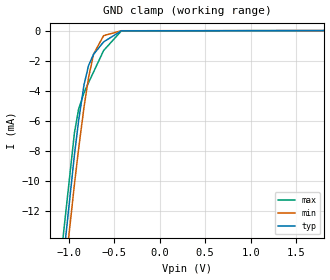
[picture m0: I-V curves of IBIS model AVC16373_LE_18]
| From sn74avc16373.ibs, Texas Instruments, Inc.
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[Model]   AVC16373_LE_18
Model_type  Input
Vinl=0.5775
Vinh=1.2675
| variable   typ   min   max
C_comp   1.18pF   0.99pF   1.35pF
[Temperature Range]   40   100   -40
| Ambient temperature   25   85   -40
[Voltage range]   1.8   1.65   1.95
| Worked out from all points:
|   GND clamp passes 1 mA (typ) near -0.65 V on its own axis
[GND Clamp]
| AVC16373_LE_18
|   Voltage   I(typ)   I(min)   I(max)
-1.8V     -63.88mA   -63.41mA   -65.81mA
-1.125V   -19.32mA   -20.97mA   -17.91mA
-1.095V   -17.47mA   -19.2mA    -15.95mA
-1.065V   -15.65mA   -17.45mA   -14.03mA
-935mV    -8.251mA   -10.21mA   -6.785mA
-890mV    -6.02mA    -7.895mA   -5.239mA
-830mV    -3.604mA   -5.085mA   -4.126mA
-780mV    -2.319mA   -3.12mA    -3.454mA
-725mV    -1.575mA   -1.563mA   -2.747mA
-615mV    -751.2uA   -336.4uA   -1.327mA
-420mV    -16.5uA    -10.21uA   -21.14uA
1.8V      199.5pA    671.8pA    9.677pA
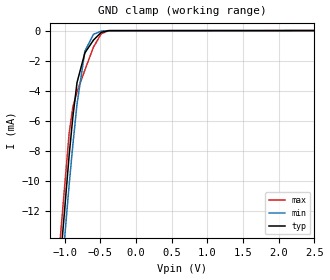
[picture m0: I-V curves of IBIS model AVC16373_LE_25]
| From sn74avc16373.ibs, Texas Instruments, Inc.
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[Model]   AVC16373_LE_25
Model_type  Input
Vinl=0.7
Vinh=1.7
| variable   typ   min   max
C_comp   1.17pF   0.97pF   1.42pF
[Temperature Range]   40   100   -40
| Ambient temperature   25   85   -40
[Voltage range]   2.5   2.3   2.7
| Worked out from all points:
|   GND clamp passes 1 mA (typ) near -0.65 V on its own axis
[GND Clamp]
| AVC16373_LE_25
|   Voltage   I(typ)   I(min)   I(max)
-2.5V     -112.2mA   -109.4mA   -117.8mA
-1.135V   -19.94mA   -21.57mA   -18.57mA
-1.1V     -17.78mA   -19.5mA    -16.27mA
-1.07V    -15.95mA   -17.74mA   -14.34mA
-935mV    -8.251mA   -10.21mA   -6.785mA
-885mV    -5.791mA   -7.647mA   -5.114mA
-825mV    -3.443mA   -4.871mA   -4.055mA
-715mV    -1.48mA    -1.36mA    -2.619mA
-595mV    -630.8uA   -252uA     -1.097mA
-485mV    -114.4uA   -29.54uA   -203.1uA
-380mV    -5.562uA   -4.599uA   -5.667uA
2.5V      206.6pA    685.3pA    11.37pA
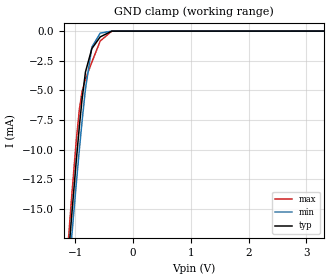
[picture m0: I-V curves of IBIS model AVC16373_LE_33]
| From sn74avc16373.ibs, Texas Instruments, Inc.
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[Model]   AVC16373_LE_33
Model_type  Input
Vinl=0.8
Vinh=2
| variable   typ   min   max
C_comp   1.17pF   0.93pF   1.44pF
[Temperature Range]   40   100   -40
| Ambient temperature   25   85   -40
[Voltage range]   3.3   3   3.6
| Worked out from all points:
|   GND clamp passes 1 mA (typ) near -0.65 V on its own axis
[GND Clamp]
| AVC16373_LE_33
|   Voltage   I(typ)   I(min)   I(max)
-3.3V     -168.4mA   -162.8mA   -178.2mA
-1.12V    -19.01mA   -20.68mA   -17.58mA
-1.1V     -17.78mA   -19.5mA    -16.27mA
-1.065V   -15.65mA   -17.45mA   -14.03mA
-985mV    -10.97mA   -12.91mA   -9.257mA
-930mV    -7.991mA   -9.944mA   -6.576mA
-885mV    -5.791mA   -7.647mA   -5.114mA
-825mV    -3.443mA   -4.871mA   -4.055mA
-715mV    -1.48mA    -1.36mA    -2.619mA
-570mV    -489.8uA   -169.9uA   -837.3uA
-370mV    -4.236uA   -3.71uA    -3.93uA
3.3V      214.2pA    699.5pA    13.28pA
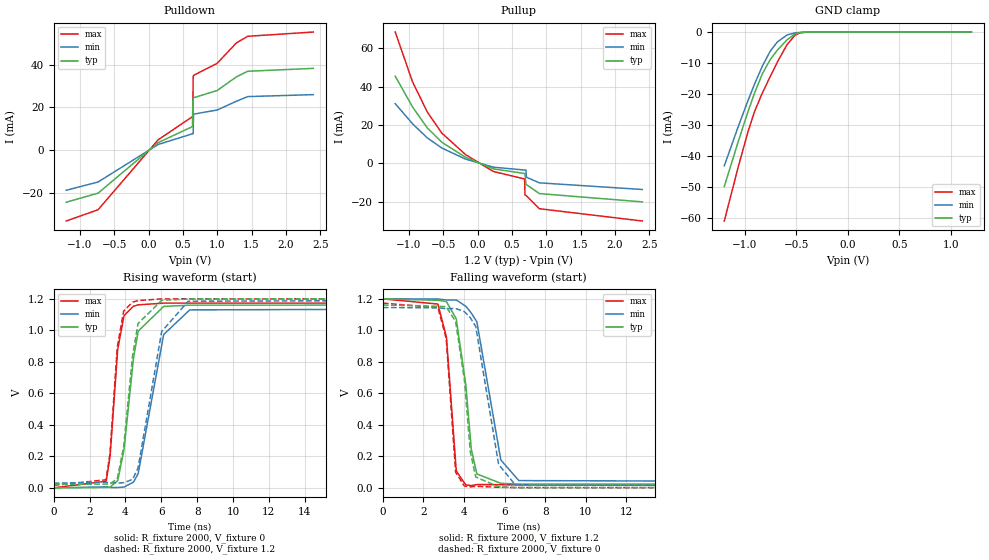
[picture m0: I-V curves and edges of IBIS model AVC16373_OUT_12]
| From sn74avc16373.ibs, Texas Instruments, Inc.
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[Model]   AVC16373_OUT_12
Model_type  3-state
Enable   Active-Low
Vref =   0
Rref =   2000
Cref =   15p
Vmeas =   0.6
| variable   typ   min   max
C_comp   4.12pF   3.33pF   5.34pF
| C_pullup   2.76pF   0.17pF   6.41pF
| C_pulldown   4.92pF   0.64pF   13.12pF
| C_tri-state   4.12pF   3.33pF   5.34pF
[Temperature Range]   40   100   -40
| Ambient temperature   25   85   -40
[Voltage range]   1.2   1.2   1.2
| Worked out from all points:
|   slope of the pulldown table from 0 to 0.18 V, typ, clamps not added: 41.3 ohm
|   slope of the pullup table from 0 to 0.18 V, typ, clamps not added: 75.9 ohm
|   GND clamp passes 1 mA (typ) near -0.53 V on its own axis
|   rising waveform, R_fixture 2000, V_fixture 0: 20-80 % time 671ps typ, 965ps min, 460ps max; typ from 0 V to 1.16 V
|   falling waveform, R_fixture 2000, V_fixture 1.2: 20-80 % time 527ps typ, 810ps min, 374ps max; typ from 1.2 V to 0.022 V
|   rising waveform, R_fixture 2000, V_fixture 1.2: 20-80 % time 659ps typ, 947ps min, 448ps max; typ from 0.022 V to 1.2 V
|   falling waveform, R_fixture 2000, V_fixture 0: 20-80 % time 493ps typ, 732ps min, 351ps max; typ from 1.16 V to 0 V
[GND Clamp]
| AVC16373_OUT_12
|   Voltage   I(typ)   I(min)   I(max)
-1.2V     -49.81mA   -43.12mA   -60.93mA
-1.065V   -35.33mA   -30.53mA   -43.53mA
-970mV    -25.69mA   -22.11mA   -32.16mA
-905mV    -19.57mA   -16.69mA   -25.52mA
-830mV    -13.44mA   -10.97mA   -19.64mA
-755mV    -8.942mA   -6.236mA   -14.44mA
-685mV    -5.853mA   -3.205mA   -9.722mA
-590mV    -2.48mA    -945.2uA   -4.03mA
-510mV    -577uA     -252.2uA   -914.9uA
-455mV    -143.2uA   -104.1uA   -185.2uA
-385mV    -21.43uA   -28.66uA   -14.82uA
1.2V      906.5pA    4.013nA    28.85pA
[Pulldown]
| AVC16373_OUT_12
|   Voltage   I(typ)   I(min)   I(max)
-1.2V     -24.58mA   -18.95mA   -33.4mA
-735mV    -20.3mA    -15.06mA   -28.1mA
140mV     3.462mA    2.573mA    4.781mA
640mV     10.98mA    7.608mA    15.63mA
645mV     21.39mA    7.616mA    15.69mA
650mV     24.35mA    7.636mA    34.23mA
655mV     24.51mA    16.53mA    34.97mA
660mV     24.57mA    16.86mA    35.1mA
1V        27.94mA    18.77mA    40.73mA
1.28V     34.34mA    22.9mA     50.3mA
1.445V    36.98mA    25.07mA    53.42mA
2.4V      38.34mA    26mA       55.42mA
[Pullup]
| AVC16373_OUT_12
|   Voltage   I(typ)   I(min)   I(max)
-1.2V     45.51mA    31.17mA    68.58mA
-950mV    29.56mA    20.73mA    42.76mA
-735mV    18.6mA     13.35mA    26.89mA
-520mV    10.96mA    7.962mA    15.74mA
-175mV    3.153mA    2.205mA    4.538mA
230mV     -2.893mA   -2.023mA   -4.269mA
685mV     -5.328mA   -3.511mA   -8.179mA
690mV     -5.367mA   -3.522mA   -16.51mA
705mV     -11.02mA   -3.556mA   -16.81mA
710mV     -11.09mA   -7.24mA    -16.92mA
900mV     -15.81mA   -10.2mA    -23.72mA
2.4V      -20.15mA   -13.67mA   -30.14mA
[Ramp]
| AVC16373_OUT_12
| variable   typ   min   max
dV/dt_r   0.70/6.79E-10   0.69/9.69E-10   0.70/4.66E-10
dV/dt_f   0.71/5.34E-10   0.70/8.12E-10   0.71/3.84E-10
R_load = 2000
[Rising Waveform]
| AVC16373_OUT_12
R_fixture =   2000
C_fixture =   0
L_fixture =   0
V_fixture =   0
V_fixture_min = 0
V_fixture_max = 0
|   Time   V(typ)   V(min)   V(max)
0s        19.84nV    111.1nV    534pV
2.925ns   2.21mV     5.753mV    42.16mV
3.14ns    4.979mV    2.339mV    201.7mV
3.565ns   45.59mV    2.125mV    879mV
3.92ns    244.4mV    5.215mV    1.094V
4.445ns   823.1mV    36.22mV    1.153V
4.71ns    995.3mV    91.19mV    1.162V
6.13ns    1.152V     973.6mV    1.173V
7.585ns   1.16V      1.13V      1.173V
50ns      1.161V     1.145V     1.173V
[Falling Waveform]
| AVC16373_OUT_12
R_fixture =   2000
C_fixture =   0
L_fixture =   0
V_fixture =   1.2
V_fixture_min = 1.2
V_fixture_max = 1.2
|   Time   V(typ)   V(min)   V(max)
0s        1.2V       1.2V       1.2V
2.71ns    1.191V     1.199V     1.167V
3.13ns    1.183V     1.193V     958.4mV
3.615ns   1.073V     1.193V     107mV
4.085ns   653.7mV    1.153V     18.34mV
4.355ns   245.5mV    1.11V      14.31mV
4.63ns    88.18mV    1.054V     21mV
5.81ns    28.72mV    177.4mV    20.03mV
6.695ns   23.88mV    46.06mV    17.94mV
50ns      22.2mV     29.57mV    16.15mV
[Rising Waveform]
| AVC16373_OUT_12
R_fixture =   2000
C_fixture =   0
L_fixture =   0
V_fixture =   1.2
V_fixture_min = 1.2
V_fixture_max = 1.2
|   Time   V(typ)   V(min)   V(max)
0s        22.2mV     29.57mV    16.15mV
2.91ns    23.93mV    35.37mV    51.16mV
3.135ns   24.73mV    31.54mV    219mV
3.54ns    57.93mV    31.01mV    891mV
3.9ns     263.1mV    32.25mV    1.123V
4.395ns   839.5mV    53.88mV    1.179V
4.7ns     1.043V     125.2mV    1.189V
6.02ns    1.191V     992.7mV    1.2V
7.5ns     1.199V     1.185V     1.2V
50ns      1.2V       1.2V       1.2V
[Falling Waveform]
| AVC16373_OUT_12
R_fixture =   2000
C_fixture =   0
L_fixture =   0
V_fixture =   0
V_fixture_min = 0
V_fixture_max = 0
|   Time   V(typ)   V(min)   V(max)
0s        1.161V     1.145V     1.173V
2.715ns   1.153V     1.143V     1.145V
3.12ns    1.15V      1.138V     946.8mV
3.585ns   1.055V     1.139V     98.97mV
4.015ns   687.3mV    1.119V     11.04mV
4.305ns   229.3mV    1.081V     6.349mV
4.575ns   68.82mV    1.024V     9.649mV
5.7ns     6.452mV    148.9mV    3.582mV
6.525ns   1.658mV    18.38mV    1.675mV
50ns      30.29nV    53.14nV    -3.408nV
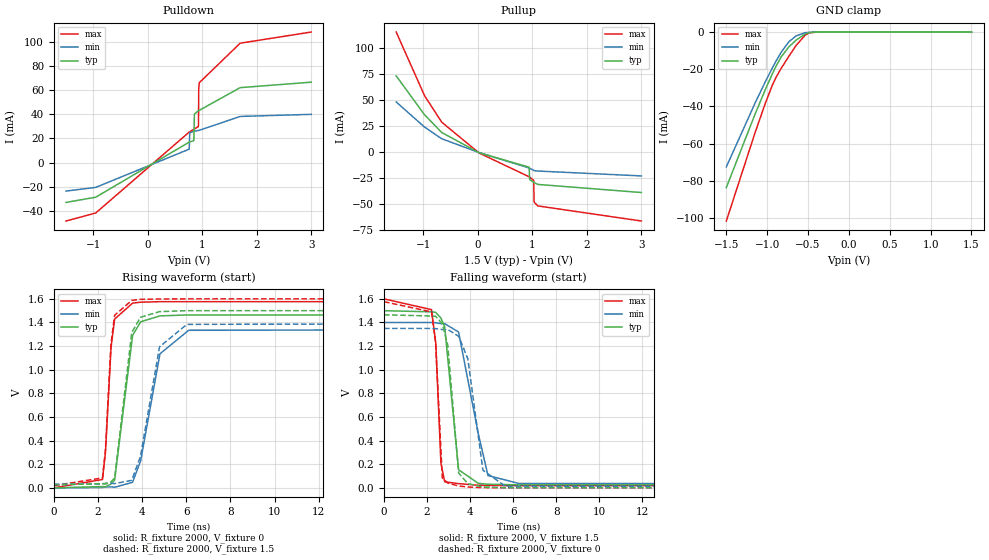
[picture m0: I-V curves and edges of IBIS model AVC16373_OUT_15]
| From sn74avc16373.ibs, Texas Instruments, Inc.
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[Model]   AVC16373_OUT_15
Model_type  3-state
Enable   Active-Low
Vref =   0
Rref =   2000
Cref =   15p
Vmeas =   0.75
| variable   typ   min   max
C_comp   4.31pF   3.38pF   5.88pF
| C_pullup   5.34pF   0.15pF   13.15pF
| C_pulldown   7.78pF   0.15pF   27.61pF
| C_tri-state   4.31pF   3.38pF   5.88pF
[Temperature Range]   40   100   -40
| Ambient temperature   25   85   -40
[Voltage range]   1.5   1.4   1.6
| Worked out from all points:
|   slope of the pulldown table from 0 to 0.225 V, typ, clamps not added: 36.1 ohm
|   slope of the pullup table from 0 to 0.225 V, typ, clamps not added: 53.5 ohm
|   GND clamp passes 1 mA (typ) near -0.53 V on its own axis
|   rising waveform, R_fixture 2000, V_fixture 0: 20-80 % time 468ps typ, 734ps min, 281ps max; typ from 0 V to 1.47 V
|   falling waveform, R_fixture 2000, V_fixture 1.5: 20-80 % time 357ps typ, 583ps min, 219ps max; typ from 1.5 V to 0.025 V
|   rising waveform, R_fixture 2000, V_fixture 1.5: 20-80 % time 452ps typ, 714ps min, 275ps max; typ from 0.025 V to 1.5 V
|   falling waveform, R_fixture 2000, V_fixture 0: 20-80 % time 346ps typ, 543ps min, 214ps max; typ from 1.47 V to 0 V
[GND Clamp]
| AVC16373_OUT_15
|   Voltage   I(typ)   I(min)   I(max)
-1.5V     -83.68mA   -72.57mA   -101.7mA
-1.15V    -44.37mA   -38.39mA   -54.38mA
-1.025V   -31.19mA   -26.93mA   -38.6mA
-940mV    -22.8mA    -19.57mA   -28.92mA
-890mV    -18.24mA   -15.49mA   -24.21mA
-830mV    -13.44mA   -10.97mA   -19.64mA
-735mV    -7.99mA    -5.222mA   -13.08mA
-645mV    -4.324mA   -2.052mA   -7.147mA
-535mV    -1.035mA   -358.6uA   -1.661mA
-485mV    -307.8uA   -166.7uA   -439.4uA
-395mV    -28.13uA   -35.17uA   -21.37uA
1.5V      923.6pA    11.37nA    28.98pA
[Pulldown]
| AVC16373_OUT_15
|   Voltage   I(typ)   I(min)   I(max)
-1.5V     -33mA      -23.61mA   -48.39mA
-955mV    -28.68mA   -20.56mA   -41.74mA
760mV     16.89mA    11.08mA    25.23mA
770mV     17.03mA    24.64mA    25.49mA
845mV     18.17mA    25.77mA    27.48mA
855mV     40.2mA     25.88mA    27.75mA
925mV     42.66mA    26.52mA    29.72mA
930mV     42.8mA     26.55mA    30.08mA
935mV     42.94mA    26.59mA    61.05mA
945mV     43.22mA    26.68mA    66.04mA
1.695V    61.97mA    38.15mA    98.75mA
3V        66.51mA    39.88mA    108mA
[Pullup]
| AVC16373_OUT_15
|   Voltage   I(typ)   I(min)   I(max)
-1.5V     73.5mA     48.38mA    115.7mA
-980mV    36.08mA    24.24mA    54.47mA
-665mV    19.05mA    13.02mA    28.99mA
20mV      -420.5uA   -275.9uA   -662.9uA
940mV     -14.35mA   -15.15mA   -23.58mA
950mV     -26.22mA   -15.4mA    -23.99mA
1.02V     -28.75mA   -17.27mA   -26.94mA
1.025V    -28.95mA   -17.41mA   -27.17mA
1.03V     -29.14mA   -17.56mA   -46.58mA
1.035V    -29.33mA   -17.7mA    -48.24mA
1.1V      -30.94mA   -18.07mA   -51.63mA
3V        -38.73mA   -22.77mA   -66.15mA
[Ramp]
| AVC16373_OUT_15
| variable   typ   min   max
dV/dt_r   0.88/4.71E-10   0.81/7.39E-10   0.95/2.88E-10
dV/dt_f   0.89/3.65E-10   0.82/5.91E-10   0.95/2.26E-10
R_load = 2000
[Rising Waveform]
| AVC16373_OUT_15
R_fixture =   2000
C_fixture =   0
L_fixture =   0
V_fixture =   0
V_fixture_min = 0
V_fixture_max = 0
|   Time   V(typ)   V(min)   V(max)
0s        20.21nV    106.8nV    637.5pV
2.205ns   10.56mV    2.702mV    70.63mV
2.34ns    8.447mV    7.294mV    300.7mV
2.595ns   32.66mV    8.339mV    1.193V
2.755ns   65.77mV    4.722mV    1.429V
3.57ns    1.291V     46.92mV    1.564V
3.935ns   1.406V     229.2mV    1.572V
4.81ns    1.456V     1.135V     1.576V
6.11ns    1.464V     1.334V     1.576V
50ns      1.465V     1.35V      1.576V
[Falling Waveform]
| AVC16373_OUT_15
R_fixture =   2000
C_fixture =   0
L_fixture =   0
V_fixture =   1.5
V_fixture_min = 1.4
V_fixture_max = 1.6
|   Time   V(typ)   V(min)   V(max)
0s        1.5V       1.4V       1.6V
2.205ns   1.49V      1.4V       1.509V
2.405ns   1.486V     1.398V     1.229V
2.645ns   1.437V     1.39V      205.8mV
2.82ns    1.364V     1.39V      51.59mV
3.465ns   153.2mV    1.319V     35.54mV
4.38ns    38.37mV    458.8mV    22.03mV
4.83ns    30.44mV    104.2mV    20.25mV
6.26ns    25.33mV    37.29mV    18.98mV
50ns      24.77mV    31.4mV     18.88mV
[Rising Waveform]
| AVC16373_OUT_15
R_fixture =   2000
C_fixture =   0
L_fixture =   0
V_fixture =   1.5
V_fixture_min = 1.4
V_fixture_max = 1.6
|   Time   V(typ)   V(min)   V(max)
0s        24.77mV    31.4mV     18.88mV
2.205ns   35.21mV    34.11mV    83.94mV
2.34ns    31.83mV    38.68mV    323.2mV
2.59ns    49.8mV     39.71mV    1.22V
2.755ns   83.91mV    35.8mV     1.461V
3.53ns    1.315V     63.65mV    1.587V
3.925ns   1.444V     264.8mV    1.596V
4.79ns    1.492V     1.194V     1.599V
6.03ns    1.5V       1.384V     1.6V
50ns      1.5V       1.4V       1.6V
[Falling Waveform]
| AVC16373_OUT_15
R_fixture =   2000
C_fixture =   0
L_fixture =   0
V_fixture =   0
V_fixture_min = 0
V_fixture_max = 0
|   Time   V(typ)   V(min)   V(max)
0s        1.465V     1.35V      1.576V
2.21ns    1.455V     1.35V      1.49V
2.4ns     1.453V     1.348V     1.222V
2.71ns    1.389V     1.34V      83.76mV
2.96ns    1.21V      1.341V     40.58mV
3.47ns    124.7mV    1.283V     15.63mV
3.895ns   35.89mV    1.093V     6.97mV
4.595ns   7.797mV    148.7mV    1.919mV
5.625ns   1.207mV    14.85mV    275.4uV
50ns      27.09nV    138.3nV    -888.7pV
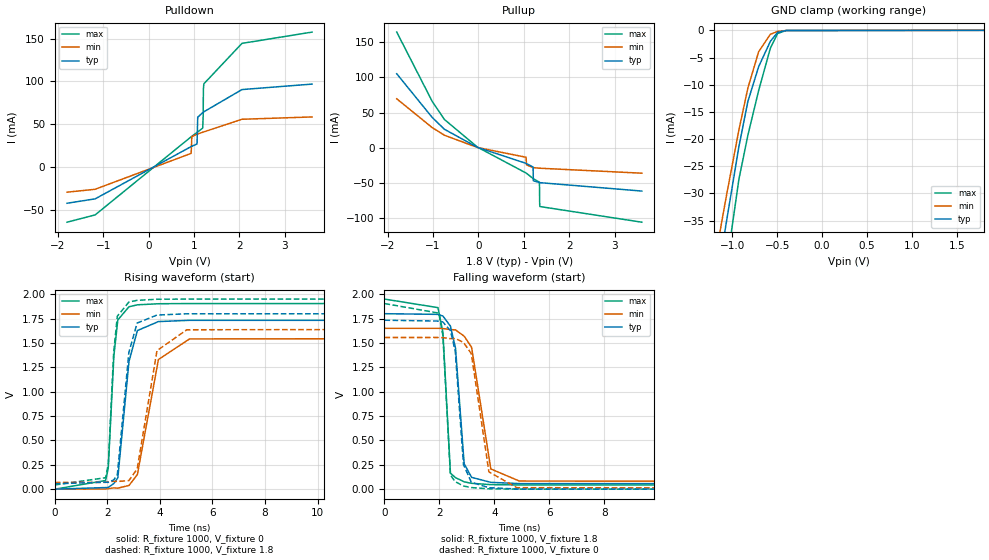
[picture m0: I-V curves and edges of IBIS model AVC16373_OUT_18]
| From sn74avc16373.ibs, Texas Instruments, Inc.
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[Model]   AVC16373_OUT_18
Model_type  3-state
Enable   Active-Low
Vref =   0
Rref =   1000
Cref =   30p
Vmeas =   0.9
| variable   typ   min   max
C_comp   4.32pF   3.35pF   5.68pF
| C_pullup   6.96pF   2.28pF   18.50pF
| C_pulldown   11.01pF   0.32pF   33.42pF
| C_tri-state   4.32pF   3.35pF   5.68pF
[Temperature Range]   40   100   -40
| Ambient temperature   25   85   -40
[Voltage range]   1.8   1.65   1.95
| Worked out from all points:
|   slope of the pulldown table from 0 to 0.27 V, typ, clamps not added: 33.5 ohm
|   slope of the pullup table from 0 to 0.27 V, typ, clamps not added: 42.5 ohm
|   GND clamp passes 1 mA (typ) near -0.53 V on its own axis
|   rising waveform, R_fixture 1000, V_fixture 0: 20-80 % time 351ps typ, 571ps min, 219ps max; typ from 0 V to 1.73 V
|   falling waveform, R_fixture 1000, V_fixture 1.8: 20-80 % time 263ps typ, 445ps min, 179ps max; typ from 1.8 V to 0.055 V
|   rising waveform, R_fixture 1000, V_fixture 1.8: 20-80 % time 330ps typ, 531ps min, 210ps max; typ from 0.055 V to 1.8 V
|   falling waveform, R_fixture 1000, V_fixture 0: 20-80 % time 253ps typ, 410ps min, 177ps max; typ from 1.73 V to 0 V
[GND Clamp]
| AVC16373_OUT_18
|   Voltage   I(typ)   I(min)   I(max)
-1.8V     -118.8mA   -103.2mA   -143.9mA
-1.215V   -51.46mA   -44.55mA   -62.92mA
-1.145V   -43.83mA   -37.92mA   -53.73mA
-1.085V   -37.42mA   -32.35mA   -46.04mA
-1.07V    -35.85mA   -30.98mA   -44.15mA
-925mV    -21.39mA   -18.32mA   -27.4mA
-825mV    -13.08mA   -10.61mA   -19.29mA
-705mV    -6.674mA   -3.926mA   -11.06mA
-575mV    -2.039mA   -729.4uA   -3.298mA
-495mV    -388.5uA   -195.8uA   -593.1uA
-400mV    -32.23uA   -38.84uA   -25.66uA
1.8V      940.2pA    10.95nA    32pA
[Pulldown]
| AVC16373_OUT_18
|   Voltage   I(typ)   I(min)   I(max)
-1.8V     -42.48mA   -29.53mA   -64.63mA
-1.18V    -37.33mA   -26.14mA   -56.11mA
935mV     23.8mA     15.87mA    35.26mA
950mV     24.14mA    35.36mA    35.83mA
1.065V    26.9mA     38.19mA    40.35mA
1.08V     58.17mA    38.51mA    40.96mA
1.19V     63.45mA    40.59mA    45.43mA
1.2V      63.85mA    40.76mA    59.33mA
1.205V    64.06mA    40.84mA    90.97mA
1.215V    64.46mA    40.99mA    97.19mA
2.055V    90.48mA    55.75mA    144.5mA
3.6V      96.88mA    58.46mA    157.7mA
[Pullup]
| AVC16373_OUT_18
|   Voltage   I(typ)   I(min)   I(max)
-1.8V     105.3mA    69.67mA    164.6mA
-1.02V    43.26mA    28.76mA    66.19mA
-750mV    26.33mA    17.87mA    40.3mA
-20mV     534.9uA    353.3uA    842.4uA
1.05V     -22.2mA    -13.51mA   -35.92mA
1.06V     -22.53mA   -24.37mA   -36.41mA
1.205V    -27.4mA    -28.2mA    -43.79mA
1.21V     -46.91mA   -28.26mA   -44.05mA
1.345V    -49.51mA   -29.08mA   -48.98mA
1.35V     -49.57mA   -29.1mA    -80.34mA
1.355V    -49.64mA   -29.12mA   -83.62mA
3.6V      -61.62mA   -36.17mA   -105.9mA
[Ramp]
| AVC16373_OUT_18
| variable   typ   min   max
dV/dt_r   1.04/3.51E-10   0.93/5.75E-10   1.14/2.25E-10
dV/dt_f   1.05/2.66E-10   0.95/4.53E-10   1.14/1.89E-10
R_load = 1000
[Rising Waveform]
| AVC16373_OUT_18
R_fixture =   1000
C_fixture =   0
L_fixture =   0
V_fixture =   0
V_fixture_min = 0
V_fixture_max = 0
|   Time   V(typ)   V(min)   V(max)
0s        21.23nV    103.7nV    761.1pV
1.935ns   16.46mV    1.53mV     88.86mV
2.035ns   17.57mV    5.439mV    214.7mV
2.25ns    58.39mV    13.35mV    1.368V
2.4ns     116.6mV    10.19mV    1.736V
2.825ns   1.311V     38.09mV    1.871V
3.145ns   1.627V     150.7mV    1.891V
3.945ns   1.719V     1.33V      1.902V
5.13ns    1.732V     1.541V     1.904V
50ns      1.733V     1.556V     1.904V
[Falling Waveform]
| AVC16373_OUT_18
R_fixture =   1000
C_fixture =   0
L_fixture =   0
V_fixture =   1.8
V_fixture_min = 1.65
V_fixture_max = 1.95
|   Time   V(typ)   V(min)   V(max)
0s        1.8V       1.65V      1.95V
1.945ns   1.793V     1.65V      1.862V
2.125ns   1.776V     1.648V     1.614V
2.4ns     1.672V     1.637V     163.7mV
2.585ns   1.446V     1.634V     118.3mV
2.9ns     260.5mV    1.569V     75.24mV
3.17ns    121.2mV    1.455V     60.09mV
3.87ns    69.85mV    207.5mV    46.58mV
4.905ns   57.18mV    83.45mV    43.4mV
50ns      55.29mV    68.18mV    43.06mV
[Rising Waveform]
| AVC16373_OUT_18
R_fixture =   1000
C_fixture =   0
L_fixture =   0
V_fixture =   1.8
V_fixture_min = 1.65
V_fixture_max = 1.95
|   Time   V(typ)   V(min)   V(max)
0s        55.29mV    68.18mV    43.06mV
1.935ns   71.56mV    69.72mV    117.6mV
2.04ns    70.2mV     73.87mV    266.7mV
2.24ns    94.73mV    81.4mV     1.396V
2.38ns    145.9mV    78.63mV    1.774V
2.82ns    1.403V     87.55mV    1.919V
3.135ns   1.704V     207.1mV    1.937V
3.89ns    1.786V     1.421V     1.948V
5.025ns   1.799V     1.635V     1.95V
50ns      1.8V       1.65V      1.95V
[Falling Waveform]
| AVC16373_OUT_18
R_fixture =   1000
C_fixture =   0
L_fixture =   0
V_fixture =   0
V_fixture_min = 0
V_fixture_max = 0
|   Time   V(typ)   V(min)   V(max)
0s        1.733V     1.556V     1.904V
1.975ns   1.724V     1.556V     1.806V
2.125ns   1.715V     1.554V     1.577V
2.4ns     1.626V     1.544V     144.4mV
2.575ns   1.415V     1.546V     76.69mV
2.875ns   252.1mV    1.506V     32.31mV
3.16ns    71.19mV    1.389V     16.38mV
3.8ns     14.91mV    177.4mV    3.774mV
4.82ns    1.805mV    15.1mV     366.1uV
50ns      34.94nV    132.6nV    -3.091nV
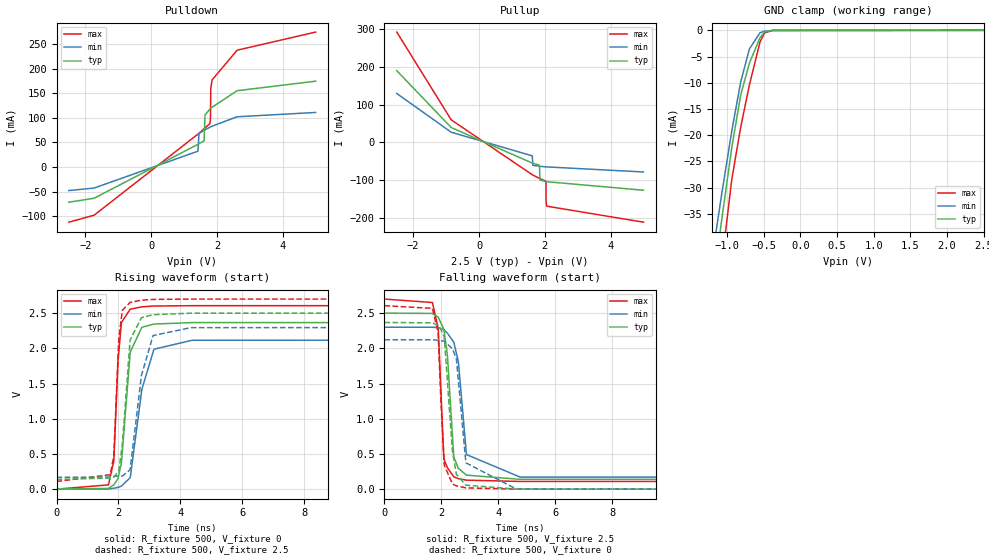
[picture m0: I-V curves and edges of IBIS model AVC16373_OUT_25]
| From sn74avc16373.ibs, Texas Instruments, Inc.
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[Model]   AVC16373_OUT_25
Model_type  3-state
Enable   Active-Low
Vref =   0
Rref =   500
Cref =   30p
Vmeas =   1.25
| variable   typ   min   max
C_comp   4.37pF   3.29pF   5.52pF
| C_pullup   7.79pF   0.82pF   27.60pF
| C_pulldown   13.36pF   1.94pF   39.56pF
| C_tri-state   4.37pF   3.29pF   5.52pF
[Temperature Range]   40   100   -40
| Ambient temperature   25   85   -40
[Voltage range]   2.5   2.3   2.7
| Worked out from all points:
|   slope of the pulldown table from 0 to 0.375 V, typ, clamps not added: 30.4 ohm
|   slope of the pullup table from 0 to 0.375 V, typ, clamps not added: 30.1 ohm
|   GND clamp passes 1 mA (typ) near -0.53 V on its own axis
|   rising waveform, R_fixture 500, V_fixture 0: 20-80 % time 244ps typ, 365ps min, 158ps max; typ from 0 V to 2.37 V
|   falling waveform, R_fixture 500, V_fixture 2.5: 20-80 % time 213ps typ, 274ps min, 140ps max; typ from 2.5 V to 0.139 V
|   rising waveform, R_fixture 500, V_fixture 2.5: 20-80 % time 228ps typ, 325ps min, 149ps max; typ from 0.139 V to 2.5 V
|   falling waveform, R_fixture 500, V_fixture 0: 20-80 % time 217ps typ, 262ps min, 142ps max; typ from 2.37 V to 0 V
[GND Clamp]
| AVC16373_OUT_25
|   Voltage   I(typ)   I(min)   I(max)
-2.5V     -203.1mA   -176.6mA   -245mA
-1.25V    -55.32mA   -47.91mA   -67.57mA
-1.22V    -52.01mA   -45.03mA   -63.58mA
-1.16V    -45.45mA   -39.33mA   -55.68mA
-1.08V    -36.9mA    -31.89mA   -45.41mA
-935mV    -22.33mA   -19.15mA   -28.4mA
-815mV    -12.4mA    -9.922mA   -18.58mA
-695mV    -6.259mA   -3.552mA   -10.39mA
-550mV    -1.378mA   -459.5uA   -2.217mA
-490mV    -343.2uA   -180.4uA   -509.8uA
-380mV    -18.7uA    -25.8uA    -12.35uA
2.5V      977.5pA    11.36nA    39.79pA
[Pulldown]
| AVC16373_OUT_25
|   Voltage   I(typ)   I(min)   I(max)
-2.5V     -71.56mA   -47.84mA   -112.1mA
-1.73V    -63.38mA   -42.71mA   -97.81mA
1.425V    46.07mA    32.15mA    66.84mA
1.455V    47.21mA    67.92mA    68.59mA
1.61V     53.02mA    74.39mA    77.73mA
1.64V     105.9mA    75.53mA    79.51mA
1.79V     117.7mA    80.88mA    88.21mA
1.805V    118.5mA    81.38mA    100.8mA
1.815V    119.1mA    81.71mA    160.3mA
1.855V    121.4mA    83mA       176.9mA
2.615V    154.9mA    102mA      237.2mA
5V        174.3mA    110.8mA    274mA
[Pullup]
| AVC16373_OUT_25
|   Voltage   I(typ)   I(min)   I(max)
-2.5V     190.4mA    129.9mA    292.9mA
-845mV    39.51mA    27.08mA    59.91mA
1.62V     -54.9mA    -35.73mA   -85.82mA
1.635V    -55.33mA   -60.76mA   -86.58mA
1.83V     -60.18mA   -63.23mA   -95.41mA
1.84V     -61.44mA   -63.34mA   -95.82mA
1.85V     -100mA     -63.44mA   -96.22mA
2.025V    -103.7mA   -64.84mA   -102.8mA
2.035V    -103.9mA   -64.9mA    -106.3mA
2.04V     -104mA     -64.93mA   -160.9mA
2.06V     -104.3mA   -65.04mA   -169.3mA
5V        -127mA     -78.45mA   -211.8mA
[Ramp]
| AVC16373_OUT_25
| variable   typ   min   max
dV/dt_r   1.42/2.47E-10   1.27/3.68E-10   1.56/1.62E-10
dV/dt_f   1.42/2.21E-10   1.28/2.77E-10   1.55/1.46E-10
R_load = 500
[Rising Waveform]
| AVC16373_OUT_25
R_fixture =   500
C_fixture =   0
L_fixture =   0
V_fixture =   0
V_fixture_min = 0
V_fixture_max = 0
|   Time   V(typ)   V(min)   V(max)
0s        25.65nV    106.5nV    1.147nV
1.675ns   10.58mV    1.953mV    60.87mV
1.85ns    60.42mV    13.51mV    401.6mV
1.985ns   150.3mV    25.38mV    1.825V
2.095ns   378.4mV    43.3mV     2.368V
2.38ns    1.949V     165.1mV    2.557V
2.755ns   2.299V     1.42V      2.59V
3.145ns   2.345V     1.988V     2.601V
4.38ns    2.366V     2.115V     2.606V
50ns      2.367V     2.122V     2.606V
[Falling Waveform]
| AVC16373_OUT_25
R_fixture =   500
C_fixture =   0
L_fixture =   0
V_fixture =   2.5
V_fixture_min = 2.3
V_fixture_max = 2.7
|   Time   V(typ)   V(min)   V(max)
0s        2.5V       2.3V       2.7V
1.685ns   2.496V     2.3V       2.651V
1.89ns    2.441V     2.293V     2.278V
2.085ns   2.272V     2.264V     429mV
2.21ns    1.907V     2.216V     306mV
2.435ns   456.1mV    2.088V     175.4mV
2.595ns   295.4mV    1.811V     149.9mV
2.88ns    199.5mV    491.4mV    127.8mV
4.765ns   139.3mV    171.4mV    109.5mV
50ns      138.6mV    167.6mV    109.3mV
[Rising Waveform]
| AVC16373_OUT_25
R_fixture =   500
C_fixture =   0
L_fixture =   0
V_fixture =   2.5
V_fixture_min = 2.3
V_fixture_max = 2.7
|   Time   V(typ)   V(min)   V(max)
0s        138.6mV    167.6mV    109.3mV
1.735ns   157.7mV    171.5mV    205.4mV
1.85ns    171.1mV    181.2mV    475.6mV
2.01ns    260.1mV    187.6mV    2.143V
2.125ns   637.6mV    186.2mV    2.541V
2.375ns   2.117V     275.6mV    2.652V
2.74ns    2.436V     1.612V     2.684V
3.115ns   2.478V     2.181V     2.695V
4.335ns   2.499V     2.294V     2.7V
50ns      2.5V       2.3V       2.7V
[Falling Waveform]
| AVC16373_OUT_25
R_fixture =   500
C_fixture =   0
L_fixture =   0
V_fixture =   0
V_fixture_min = 0
V_fixture_max = 0
|   Time   V(typ)   V(min)   V(max)
0s        2.367V     2.122V     2.606V
1.685ns   2.363V     2.122V     2.568V
1.885ns   2.328V     2.115V     2.232V
1.985ns   2.265V     2.108V     1.23V
2.1ns     2.164V     2.102V     342.4mV
2.385ns   551mV      1.995V     74.99mV
2.525ns   212mV      1.856V     46.36mV
2.86ns    57mV       374.4mV    18.33mV
4.62ns    839.1uV    4.183mV    212.1uV
50ns      23.47nV    112.5nV    -2.55nV
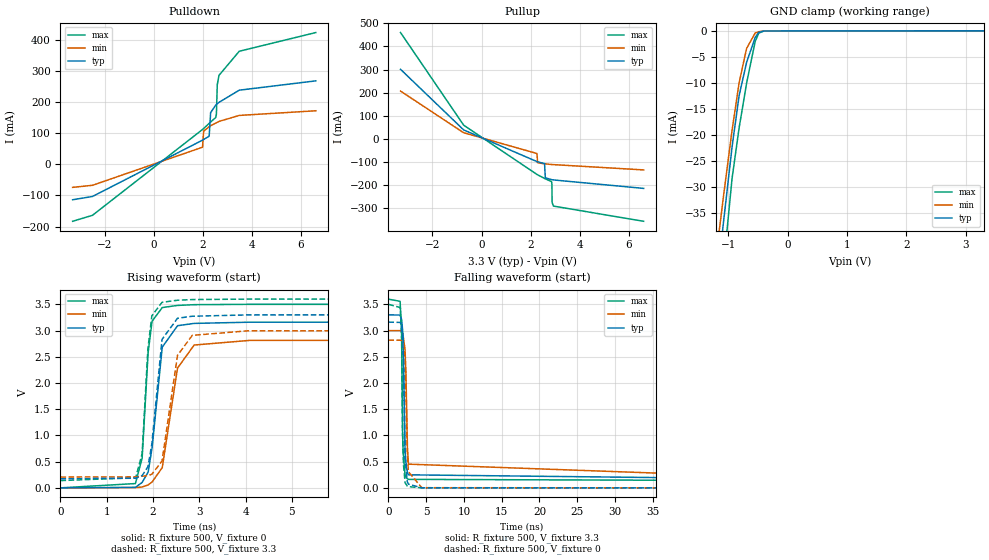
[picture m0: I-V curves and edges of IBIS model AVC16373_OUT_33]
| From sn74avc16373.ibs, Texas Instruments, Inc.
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[Model]   AVC16373_OUT_33
Model_type  3-state
Enable   Active-Low
Vref =   0
Rref =   500
Cref =   30p
Vmeas =   1.65
| variable   typ   min   max
C_comp   4.29pF   3.26pF   5.42pF
| C_pullup   8.98pF   1.04pF   34.15pF
| C_pulldown   14.42pF   3.21pF   43.06pF
| C_tri-state   4.29pF   3.26pF   5.42pF
[Temperature Range]   40   100   -40
| Ambient temperature   25   85   -40
[Voltage range]   3.3   3   3.6
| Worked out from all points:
|   slope of the pulldown table from 0 to 0.495 V, typ, clamps not added: 28.5 ohm
|   slope of the pullup table from 0 to 0.495 V, typ, clamps not added: 23.7 ohm
|   GND clamp passes 1 mA (typ) near -0.53 V on its own axis
|   rising waveform, R_fixture 500, V_fixture 0: 20-80 % time 204ps typ, 284ps min, 136ps max; typ from 0 V to 3.16 V
|   falling waveform, R_fixture 500, V_fixture 3.3: 20-80 % time 202ps typ, 249ps min, 159ps max; typ from 3.3 V to 0.173 V
|   rising waveform, R_fixture 500, V_fixture 3.3: 20-80 % time 193ps typ, 259ps min, 130ps max; typ from 0.173 V to 3.3 V
|   falling waveform, R_fixture 500, V_fixture 0: 20-80 % time 201ps typ, 257ps min, 171ps max; typ from 3.16 V to 0 V
[GND Clamp]
| AVC16373_OUT_33
|   Voltage   I(typ)   I(min)   I(max)
-3.3V     -301.3mA   -262.3mA   -362.9mA
-1.23V    -53.11mA   -45.98mA   -64.91mA
-1.175V   -47.08mA   -40.74mA   -57.65mA
-1.15V    -44.37mA   -38.39mA   -54.38mA
-1.08V    -36.9mA    -31.89mA   -45.41mA
-935mV    -22.33mA   -19.15mA   -28.4mA
-815mV    -12.4mA    -9.922mA   -18.58mA
-690mV    -6.055mA   -3.375mA   -10.05mA
-545mV    -1.259mA   -420.4uA   -2.023mA
-485mV    -307.8uA   -166.7uA   -439.4uA
-395mV    -28.14uA   -35.17uA   -21.37uA
3.3V      1.018nA    11.16nA    48.31pA
[Pulldown]
| AVC16373_OUT_33
|   Voltage   I(typ)   I(min)   I(max)
-3.3V     -113.7mA   -73.92mA   -182.8mA
-2.49V    -103.1mA   -67.29mA   -163.5mA
1.99V     77.64mA    55mA       111.9mA
2.035V    79.8mA     106.5mA    115.2mA
2.26V     90.24mA    120.9mA    131.5mA
2.32V     166.2mA    123.7mA    135.8mA
2.53V     190.2mA    132.7mA    150.5mA
2.555V    191.9mA    133.7mA    161.2mA
2.59V     194.3mA    135mA      255.5mA
2.66V     198.9mA    137.7mA    285.6mA
3.485V    238mA      157mA      362.9mA
6.6V      267.9mA    171.9mA    422.9mA
[Pullup]
| AVC16373_OUT_33
|   Voltage   I(typ)   I(min)   I(max)
-3.3V     300.9mA    206.8mA    459.7mA
-730mV    38.94mA    26.73mA    59.5mA
2.255V    -98.11mA   -63.13mA   -153.5mA
2.28V     -98.9mA    -103mA     -155mA
2.565V    -106.8mA   -107.8mA   -170.9mA
2.595V    -168.1mA   -108.1mA   -172.4mA
2.85V     -176mA     -110.5mA   -184.7mA
2.865V    -176.3mA   -110.6mA   -197.1mA
2.87V     -176.4mA   -110.7mA   -265.4mA
2.875V    -176.5mA   -110.7mA   -275.7mA
2.925V    -177.3mA   -111.1mA   -290.3mA
6.6V      -213.9mA   -134mA     -356.1mA
[Ramp]
| AVC16373_OUT_33
| variable   typ   min   max
dV/dt_r   1.90/2.13E-10   1.69/2.87E-10   2.10/1.41E-10
dV/dt_f   1.88/2.08E-10   1.68/2.56E-10   2.08/1.63E-10
R_load = 500
[Rising Waveform]
| AVC16373_OUT_33
R_fixture =   500
C_fixture =   0
L_fixture =   0
V_fixture =   0
V_fixture_min = 0
V_fixture_max = 0
|   Time   V(typ)   V(min)   V(max)
0s        34.29nV    120.2nV    1.957nV
1.62ns    10.34mV    3.786mV    81.84mV
1.765ns   102.7mV    16.06mV    566.5mV
1.895ns   300.5mV    55.3mV     2.584V
1.98ns    762.5mV    111mV      3.179V
2.2ns     2.684V     386.1mV    3.439V
2.53ns    3.093V     2.285V     3.48V
2.89ns    3.137V     2.724V     3.494V
4.085ns   3.16V      2.813V     3.501V
50ns      3.161V     2.817V     3.501V
[Falling Waveform]
| AVC16373_OUT_33
R_fixture =   500
C_fixture =   0
L_fixture =   0
V_fixture =   3.3
V_fixture_min = 3
V_fixture_max = 3.6
|   Time   V(typ)   V(min)   V(max)
0s        3.3V       3V         3.6V
1.555ns   3.296V     2.999V     3.558V
1.755ns   3.212V     2.991V     2.933V
1.88ns    3.015V     2.956V     1.084V
1.95ns    2.882V     2.907V     714mV
2.205ns   752mV      2.637V     246.6mV
2.32ns    494mV      2.219V     204.7mV
2.53ns    290.8mV    735mV      172.2mV
2.655ns   248.6mV    452.2mV    161.8mV
50ns      173.2mV    206mV      138.4mV
[Rising Waveform]
| AVC16373_OUT_33
R_fixture =   500
C_fixture =   0
L_fixture =   0
V_fixture =   3.3
V_fixture_min = 3
V_fixture_max = 3.6
|   Time   V(typ)   V(min)   V(max)
0s        173.2mV    206mV      138.4mV
1.625ns   184mV      210.1mV    193.4mV
1.765ns   233.3mV    222.1mV    652.4mV
1.89ns    401.4mV    231.9mV    2.655V
1.975ns   837.5mV    260mV      3.282V
2.195ns   2.832V     510.6mV    3.539V
2.53ns    3.235V     2.53V      3.579V
2.85ns    3.274V     2.909V     3.592V
4.06ns    3.299V     2.996V     3.6V
50ns      3.3V       3V         3.6V
[Falling Waveform]
| AVC16373_OUT_33
R_fixture =   500
C_fixture =   0
L_fixture =   0
V_fixture =   0
V_fixture_min = 0
V_fixture_max = 0
|   Time   V(typ)   V(min)   V(max)
0s        3.161V     2.817V     3.501V
1.575ns   3.156V     2.816V     3.44V
1.755ns   3.1V       2.809V     2.853V
1.88ns    2.916V     2.79V      1.011V
2ns       2.511V     2.722V     444.4mV
2.215ns   566.1mV    2.488V     97.99mV
2.505ns   116.6mV    709.5mV    35.21mV
2.645ns   70.72mV    311.5mV    23.27mV
4.425ns   776.6uV    2.997mV    -52.56uV
50ns      32.82nV    120.6nV    -2.328nV
